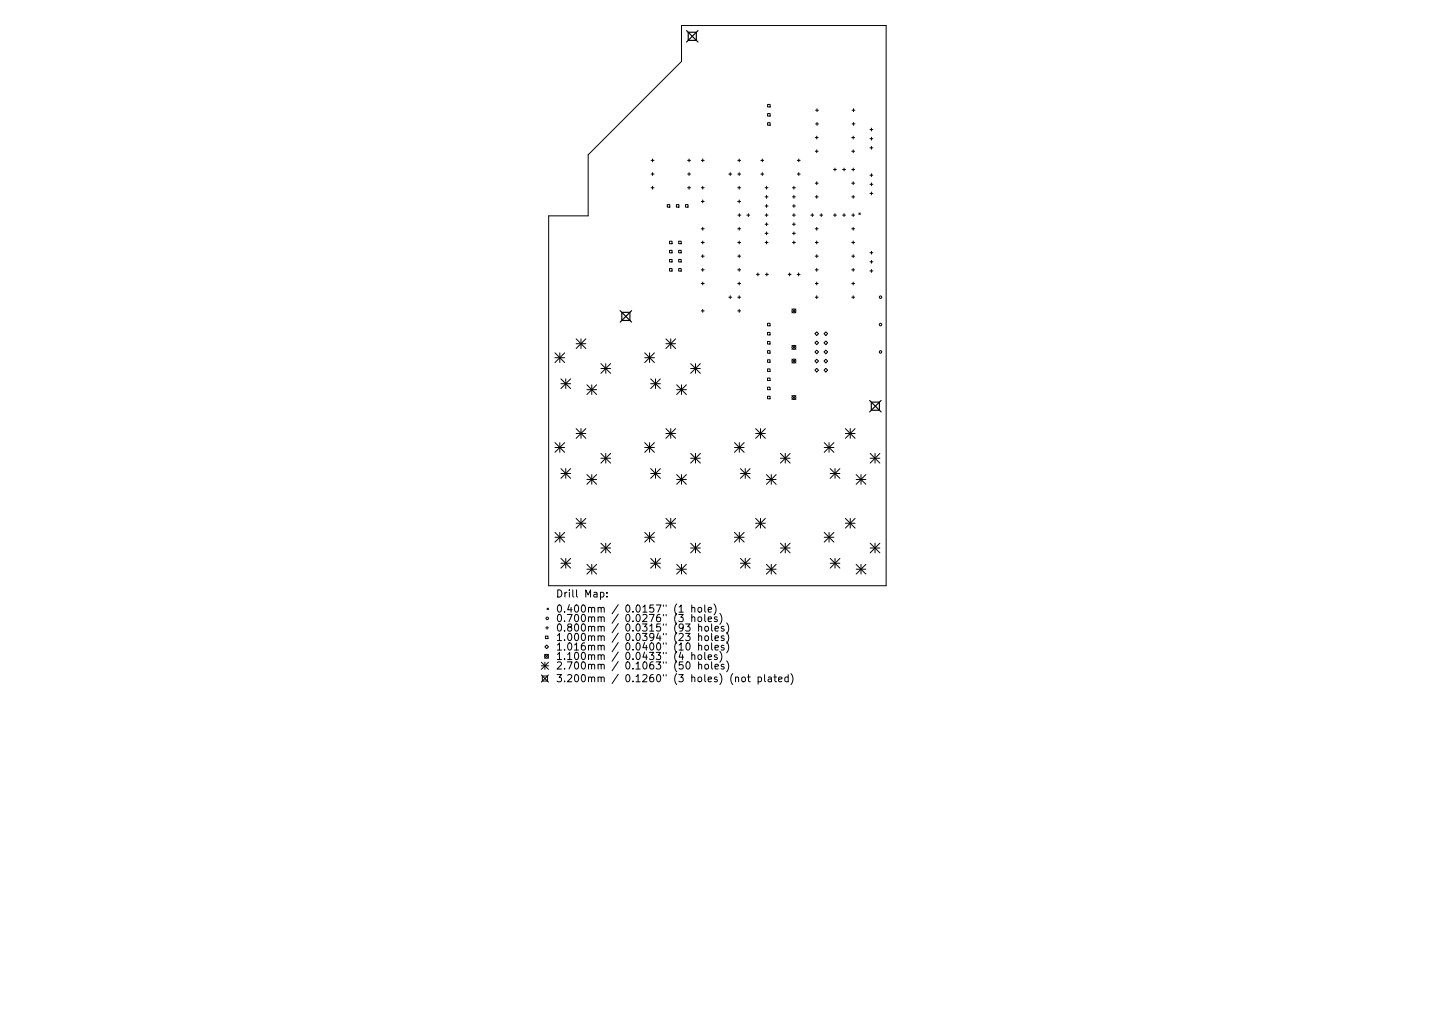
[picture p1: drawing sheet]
<svg xmlns="http://www.w3.org/2000/svg" width="297mm" height="210mm" viewBox="0 0 297 210" stroke-linecap="round" stroke-linejoin="round" font-family="sans-serif">
<defs><g id="words">
<g font-size="2.1">
<text x="115" y="123.6">Drill Map:</text>
<text x="115" y="126.8">0.400mm / 0.0157&quot; (1 hole)</text>
<text x="115" y="128.7">0.700mm / 0.0276&quot; (3 holes)</text>
<text x="115" y="130.7">0.800mm / 0.0315&quot; (93 holes)</text>
<text x="115" y="132.6">1.000mm / 0.0394&quot; (23 holes)</text>
<text x="115" y="134.6">1.016mm / 0.0400&quot; (10 holes)</text>
<text x="115" y="136.6">1.100mm / 0.0433&quot; (4 holes)</text>
<text x="115" y="138.5">2.700mm / 0.1063&quot; (50 holes)</text>
<text x="115" y="141.2">3.200mm / 0.1260&quot; (3 holes) (not plated)</text>
</g>
</g></defs>
<g fill="none" stroke="#000" stroke-width=".21">
<path d="M141.1 5.3h42.3v115.9h-69.8v-76.5h8.1v-12.7l19.4-19.3zM134.8 33.2h.6M134.8 36h.6M134.8 38.9h.6M135.1 32.9v.6M135.1 35.7v.6M135.1 38.6v.6M142.3 33.2h.6M142.3 36h.6M142.3 38.9h.6M142.6 32.9v.6M142.6 35.7v.6"/>
<path d="M142.6 38.6v.6M145.2 33.2h.6M145.2 38.9h.6M145.5 32.9v.6M145.5 38.6v.6M150.9 36h.6M151.2 35.7v.6M152.7 33.2h.6M152.7 36h.6M152.7 38.9h.6M153 32.9v.6M153 35.7v.6"/>
<path d="M153 38.6v.6M157.5 33.2h.6M157.5 36h.6M157.8 32.9v.6M157.8 35.7v.6M158.4 38.9h.6M158.7 38.6v.6M158.9 21.6h.5v.5h-.5zM158.9 23.5h.5v.5h-.5zM158.9 25.4h.5v.5h-.5zM164 38.9h.6M164.3 38.6v.6"/>
<path d="M165 33.2h.6M165 36h.6M165.3 32.9v.6M165.3 35.7v.6M168.8 28.5h.6M168.8 31.3h.6M168.8 37.9h.6M168.8 22.8h.6M168.8 25.6h.6M169.1 28.2v.6M169.1 31v.6M169.1 37.6v.6"/>
<path d="M169.1 22.5v.6M169.1 25.3v.6M172.5 35.1h.6M172.8 34.8v.6M174.4 35.1h.6M174.7 34.8v.6M176.3 28.5h.6M176.3 31.3h.6M176.3 37.9h.6M176.3 35.1h.6M176.4 22.8h.6M176.4 25.6h.6"/>
<path d="M176.6 28.2v.6M176.6 31v.6M176.6 34.8v.6M176.6 37.6v.6M176.7 22.5v.6M176.7 25.3v.6M180.1 26.8h.6M180.1 28.7h.6M180.1 30.6h.6M180.1 36.3h.6M180.1 38.1h.6M180.4 26.5v.6"/>
<path d="M180.4 28.4v.6M180.4 30.3v.6M180.4 36v.5M180.4 37.8v.6M180.4 39.7v.6M138.1 42.3h.5v.6h-.5zM138.6 49.9h.5v.5h-.5zM138.6 51.8h.5v.5h-.5zM138.6 53.7h.5v.5h-.5zM138.6 55.6h.5v.5h-.5zM140 42.3h.5v.6h-.5zM140.5 49.9h.5v.5h-.5z"/>
<path d="M140.5 51.8h.5v.5h-.5zM140.5 53.7h.5v.5h-.5zM140.5 55.6h.5v.5h-.5zM141.9 42.3h.5v.6h-.5zM145.2 41.7h.6M145.2 47.3h.6M145.2 50.2h.6M145.2 53h.6M145.2 55.8h.6M145.2 58.7h.6M145.5 41.4v.6M145.5 47.1v.5"/>
<path d="M145.5 49.9v.6M145.5 52.7v.6M145.5 55.5v.6M145.5 58.4v.6M152.7 41.7h.6M152.7 47.3h.6M152.7 50.2h.6M152.7 53h.6M152.7 55.8h.6M152.7 58.7h.6M152.7 44.5h.6M153 41.4v.6"/>
<path d="M153 47.1v.5M153 49.9v.6M153 52.7v.6M153 55.5v.6M153 58.4v.6M153 44.2v.6M154.6 44.5h.6M154.9 44.2v.6M156.6 56.8h.6M156.9 56.5v.6M158.4 50.2h.6M158.4 44.5h.6"/>
<path d="M158.4 40.7h.6M158.4 42.6h.6M158.4 46.4h.6M158.4 48.3h.6M158.4 56.8h.6M158.7 40.4v.6M158.7 42.3v.6M158.7 44.2v.6M158.7 46.1v.6M158.7 48v.6M158.7 49.9v.6M158.7 56.5v.6"/>
<path d="M163.2 56.8h.6M163.5 56.5v.6M164 50.2h.6M164 44.5h.6M164 40.7h.6M164 42.6h.6M164 46.4h.6M164 48.3h.6M164.3 40.4v.6M164.3 42.3v.6M164.3 44.2v.6M164.3 46.1v.6"/>
<path d="M164.3 48v.6M164.3 49.9v.6M165 56.8h.6M165.3 56.5v.6M167.8 44.5h.6M168.1 44.2v.6M168.8 47.3h.6M168.8 50.2h.6M168.8 53h.6M168.8 55.8h.6M168.8 58.7h.6M168.8 40.7h.6"/>
<path d="M169.1 40.4v.6M169.1 47.1v.5M169.1 49.9v.6M169.1 52.7v.6M169.1 55.5v.6M169.1 58.4v.6M169.7 44.5h.6M170 44.2v.6M172.5 44.5h.6M172.8 44.2v.6M174.4 44.5h.6M174.7 44.2v.6"/>
<path d="M176.3 47.3h.6M176.3 50.2h.6M176.3 53h.6M176.3 55.8h.6M176.3 58.7h.6M176.3 44.5h.6M176.3 40.7h.6M176.6 40.4v.6M176.6 44.2v.6M176.6 47.1v.5M176.6 49.9v.6M176.6 52.7v.6"/>
<path d="M176.6 55.5v.6M176.6 58.4v.6M177.8 44.1l.3 .3M178.1 44.1l-.3 .3M180.1 40h.6M180.1 52.3h.6M180.1 54.2h.6M180.1 56.1h.6M180.4 52v.6M180.4 53.9v.6M180.4 55.8v.6M114.9 73l2 2"/>
<path d="M114.9 74h2M115.9 73v2M116.1 78.4l2 2M116.1 79.4h2M116.9 73l-2 2M117.1 78.4v2M118.1 78.4l-2 2M119.3 70.1l2 2M119.3 71.1h2M120.3 70.1v2M121.3 70.1l-2 2M121.5 79.6l2 2"/>
<path d="M122.5 79.6v2M123.5 79.6l-2 2M124.4 75.3l2 2M124.4 76.3h2M125.4 75.3v2M126.4 75.3l-2 2M133.5 74h2M133.5 73l2 2M134.5 73v2M134.7 79.4h2M134.7 78.4l2 2M135.5 73l-2 2"/>
<path d="M135.7 78.4v2M136.7 78.4l-2 2M137.8 71.1h2M137.8 70.1l2 2M138.8 70.1v2M139.8 70.1l-2 2M140.1 79.6l2 2M141.1 79.6v2M142.1 79.6l-2 2M143 76.3h2M143 75.3l2 2M144 75.3v2"/>
<path d="M145 75.3l-2 2M145.2 64.3h.6M145.5 64v.6M150.9 61.5h.6M151.2 61.2v.6M152.7 64.3h.6M152.7 61.5h.6M153 61.2v.6M153 64v.6M158.9 66.9h.5v.5h-.5zM158.9 68.8h.5v.5h-.5zM158.9 70.7h.5v.5h-.5z"/>
<path d="M158.9 72.6h.5v.5h-.5zM158.9 74.5h.5v.5h-.5zM158.9 76.3h.5v.6h-.5zM158.9 78.2h.5v.6h-.5zM163.9 63.9l.8 .8M163.9 71.5l.8 .8M163.9 74.3l.8 .8M164.7 63.9l-.8 .8M164.7 71.5l-.8 .8M164.7 74.3l-.8 .8M168.7 69.1l.4-.4 .3 .4-.3 .3zM168.7 70.9l.4-.3 .3 .3-.3 .4z"/>
<path d="M168.7 74.7l.4-.4 .3 .4-.3 .4zM168.7 76.6l.4-.4 .3 .4-.3 .4zM168.8 61.5h.6M169.1 72.5l.3 .3-.3 .4-.4-.4zM169.1 61.2v.6M170.6 69.1l.3-.4 .4 .4-.4 .3zM170.6 70.9l.3-.3 .4 .3-.4 .4zM170.6 72.8l.3-.3 .4 .3-.4 .4zM170.6 74.7l.3-.4 .4 .4-.4 .4zM170.6 76.6l.3-.4 .4 .4-.4 .4zM176.3 61.5h.6M176.6 61.2v.6"/>
<path d="M114.9 91.6l2 2M114.9 92.6h2M115.9 91.6v2M116.1 97l2 2M116.1 98h2M116.9 91.6l-2 2M117.1 97v2M118.1 97l-2 2M119.3 88.7l2 2M119.3 89.7h2M120.3 88.7v2M121.3 88.7l-2 2"/>
<path d="M121.5 98.2l2 2M121.5 80.6h2M121.5 99.2h2M122.5 98.2v2M123.5 98.2l-2 2M124.4 93.8l2 2M124.4 94.8h2M125.4 93.8v2M126.4 93.8l-2 2M133.5 91.6l2 2M133.5 92.6h2M134.5 91.6v2"/>
<path d="M134.7 97l2 2M134.7 98h2M135.5 91.6l-2 2M135.7 97v2M136.7 97l-2 2M137.8 89.7h2M137.8 88.7l2 2M138.8 88.7v2M139.8 88.7l-2 2M140.1 80.6h2M140.1 99.2h2M140.1 98.2l2 2"/>
<path d="M141.1 98.2v2M142.1 98.2l-2 2M143 94.8h2M143 93.8l2 2M144 93.8v2M145 93.8l-2 2M152 92.6h2M152 91.6l2 2M153 91.6v2M153.3 98h2M153.3 97l2 2M154 91.6l-2 2"/>
<path d="M154.3 97v2M155.3 97l-2 2M156.4 89.7h2M156.4 88.7l2 2M157.4 88.7v2M158.4 88.7l-2 2M158.6 99.2h2.1M158.6 98.2l2.1 2M158.9 80.1h.5v.5h-.5zM158.9 82h.5v.5h-.5zM159.6 98.2v2M160.7 98.2l-2.1 2"/>
<path d="M161.5 94.8h2M161.5 93.8l2 2M162.5 93.8v2M163.5 93.8l-2 2M163.9 81.9l.8 .8M164.7 81.9l-.8 .8M170.6 92.6h2M170.6 91.6l2 2M171.6 91.6v2M171.8 98h2M171.8 97l2 2M172.6 91.6l-2 2"/>
<path d="M172.8 97v2M173.8 97l-2 2M175 89.7h2M175 88.7l2 2M176 88.7v2M177 88.7l-2 2M177.2 99.2h2M177.2 98.2l2 2M178.2 98.2v2M179.2 98.2l-2 2M180.1 94.8h2M180.1 93.8l2 2"/>
<path d="M181.1 93.8v2M182.1 93.8l-2 2M114.9 110.2l2 2M114.9 111.2h2M115.9 110.2v2M116.1 115.6l2 2M116.1 116.6h2M116.9 110.2l-2 2M117.1 115.6v2M118.1 115.6l-2 2M119.3 107.3l2 2M119.3 108.3h2"/>
<path d="M120.3 107.3v2M121.3 107.3l-2 2M121.5 116.8l2 2M121.5 117.8h2M122.5 116.8v2M123.5 116.8l-2 2M124.4 112.4l2 2M124.4 113.4h2M125.4 112.4v2M126.4 112.4l-2 2M133.5 111.2h2M133.5 110.2l2 2"/>
<path d="M134.5 110.2v2M134.7 115.6l2 2M134.7 116.6h2M135.5 110.2l-2 2M135.7 115.6v2M136.7 115.6l-2 2M137.8 108.3h2M137.8 107.3l2 2M138.8 107.3v2M139.8 107.3l-2 2M140.1 117.8h2M140.1 116.8l2 2"/>
<path d="M141.1 116.8v2M142.1 116.8l-2 2M143 112.4l2 2M143 113.4h2M144 112.4v2M145 112.4l-2 2M152 111.2h2M152 110.2l2 2M153 110.2v2M153.3 116.6h2M153.3 115.6l2 2M154 110.2l-2 2"/>
<path d="M154.3 115.6v2M155.3 115.6l-2 2M156.4 108.3h2M156.4 107.3l2 2M157.4 107.3v2M158.4 107.3l-2 2M158.6 117.8h2.1M158.6 116.8l2.1 2M159.6 116.8v2M160.7 116.8l-2.1 2M161.5 113.4h2M161.5 112.4l2 2"/>
<path d="M162.5 112.4v2M163.5 112.4l-2 2M170.6 111.2h2M170.6 110.2l2 2M171.6 110.2v2M171.8 116.6h2M171.8 115.6l2 2M172.6 110.2l-2 2M172.8 115.6v2M173.8 115.6l-2 2M175 108.3h2M175 107.3l2 2"/>
<path d="M176 107.3v2M177 107.3l-2 2M177.2 117.8h2M177.2 116.8l2 2M178.2 116.8v2M179.2 116.8l-2 2M180.1 113.4h2M180.1 112.4l2 2M181.1 112.4v2M182.1 112.4l-2 2M112 137l1.5 1.5M112 137.8h1.5"/>
<path d="M112 139.7l1.5 1.5M112.3 139.9h1v1h-1zM112.7 135.4l.8 .8M112.8 133.9l.4-.4 .3 .4-.3 .3zM112.8 137v1.5M112.9 131.6h.5v.6h-.5zM112.9 129.9h.6M113.2 125.9l.3 .3M113.2 129.6v.6M113.5 125.9l-.3 .3M113.5 135.4l-.8 .8M113.5 137l-1.5 1.5"/>
<path d="M113.5 139.7l-1.5 1.5M124.3 122.6h.4l.3 .3-.1 .6h-.6M125.6 123.4v.2M125.6 122.6v.2M140.6 125.6l.4-.4v1.5M141.9 129.1h.9l-.5 .6 .5 .1v.7l-.2 .1-.7-.1M141.9 131.1h.9l-.5 .5 .5 .2v.6l-.2 .2-.7-.2M142.1 137.1l.2-.1a.79 .79 0 0 1 .6 .7 .79 .79 0 0 1-.6 .8l-.2-.2-.1-.4zM142.2 133.1l.1-.1a.79 .79 0 0 1 .6 .8 .79 .79 0 0 1-.6 .7 .99 .99 0 0 1-.1-1.4zM143.2 125.8l.2-.1 .4 .1v.9M143.2 127.8l.2-.1h.4v.9M143.2 135.6l.2-.1 .4 .1v.9"/>
<path d="M143.2 125.2v1.5M143.2 127.2v1.4M143.2 135v1.5M144.5 127.8l.3-.1 .4 .1v.6l-.1 .2h-.3l-.3-.1zM144.5 135.6l.3-.1 .4 .1v.6l-.1 .2-.3 .1-.3-.2zM144.6 125.8l.4-.1 .2 .3v.4l-.2 .3-.4-.1-.1-.2zM144.6 129.8l.2-.2 .4 .1v.9M144.6 131.7l.2-.1h.4v1M144.6 133.7l.2-.2 .4 .1v.9M144.6 137.6l.2-.1h.4v1M144.6 129.1v1.5M144.6 131.1v1.5"/>
<path d="M144.6 133v1.5M144.6 137v1.5M145.9 125.2v1.3l.2 .2M145.9 127.2v1.2l.2 .2M145.9 135v1.3l.2 .2M146 129.7l.4-.1 .3 .3v.4l-.3 .3-.4-.1-.1-.2zM146 131.6h.4l.3 .3v.4l-.3 .3-.4-.1-.1-.2zM146 133.6l.4-.1 .3 .3v.4l-.3 .3h-.4l-.1-.3zM146 137.5h.4l.3 .2v.5l-.3 .3-.4-.1-.1-.2zM146.6 126.2l.7-.2-.1-.2-.4-.1-.2 .2 .1 .7h.5M146.6 128.1l.7-.1-.1-.3h-.4l-.2 .2 .1 .7h.5M146.6 136l.7-.1-.1-.3-.4-.1-.2 .2 .1 .7h.5"/>
<path d="M147.3 129.1v1.3l.2 .2M147.3 131.1v1.3l.2 .2M147.3 133v1.3l.2 .2M147.3 137v1.2l.2 .3M147.8 125a1.7 1.7 0 0 1 0 2.2M148 130.1l.7-.1-.1-.3-.4-.1-.2 .2 .1 .7h.5M148 132.1l.7-.2-.1-.3h-.4l-.2 .2 .1 .7h.5M148 134l.7-.1-.1-.3-.4-.1-.2 .2 .1 .8h.5M148 138l.7-.2-.1-.3h-.4l-.2 .2 .1 .7h.5M148.4 127.7h-.3l-.2 .2v.2l.5 .1v.4h-.5M148.4 135.6l-.3-.1-.2 .2v.2l.5 .2v.3h-.5M149 126.9a1.7 1.7 0 0 1 0 2.3"/>
<path d="M149 134.8a1.7 1.7 0 0 1 0 2.3M149.8 129.7l-.3-.1-.2 .2 .1 .2 .4 .2v.3h-.5M149.8 131.6h-.3l-.2 .2 .1 .2 .4 .1v.4h-.5M149.8 133.6l-.3-.1-.2 .2 .1 .3 .4 .1v.4h-.5M149.8 137.5h-.3l-.2 .2 .1 .2 .4 .1v.4h-.5M150.4 128.9a1.7 1.7 0 0 1 0 2.3M150.4 130.9a1.7 1.7 0 0 1 0 2.2M150.4 132.8a1.7 1.7 0 0 1 0 2.3M150.4 136.8a1.7 1.7 0 0 1 0 2.2M154.9 139.6v1.3l.4 .2M158.3 139.6v1.3l.2 .2M160.4 139.6v1.3l.3 .2"/>
<path d="M163.2 139.6v1.5M163.7 139.4a1.7 1.7 0 0 1 0 2.3M152.3 140.2l.2-.1 .3 .1 .1 .9M153.6 140.2l.2-.1 .4 .1 .1 .6-.1 .2-.4 .1-.2-.2zM154.7 140.1h.6M156.9 140.2l.4-.1 .3 .3-.1 .6h-.6M156.9 140.1v1.5M159 140.2h.6l.1 .9M159.7 140.5h-.5l-.2 .2 .2 .4 .5-.1M160.2 140.1h.5M161.2 140.6l.7-.1-.1-.3-.4-.1-.2 .2v.7h.6M163.2 140.2l-.5-.1-.3 .3 .2 .6h.6"/>
<circle cx="164.3" cy="74.7" r=".41"/>
<circle cx="164.3" cy="71.9" r=".41"/>
<circle cx="164.3" cy="64.3" r=".41"/>
<circle cx="182.3" cy="61.5" r=".26"/>
<circle cx="182.3" cy="67.2" r=".26"/>
<circle cx="182.3" cy="72.8" r=".26"/>
<circle cx="164.3" cy="82.3" r=".41"/>
<circle cx="113.1" cy="135.8" r=".41"/>
<circle cx="113.3" cy="128" r=".26"/>
</g>
<path d="M142.1 6.3l2.4 2.4M142.5 6.7h1.6v1.7h-1.6zM144.5 6.3l-2.4 2.4M128.4 64.3l2.3 2.4M128.7 64.6h1.7v1.7h-1.7zM130.7 64.3l-2.3 2.4M180 82.9l2.4 2.3M180.4 83.2h1.6v1.7h-1.6zM182.4 82.9l-2.4 2.3" fill="none" stroke="#000" stroke-width=".24"/>
<use href="#words"/>
</svg>
